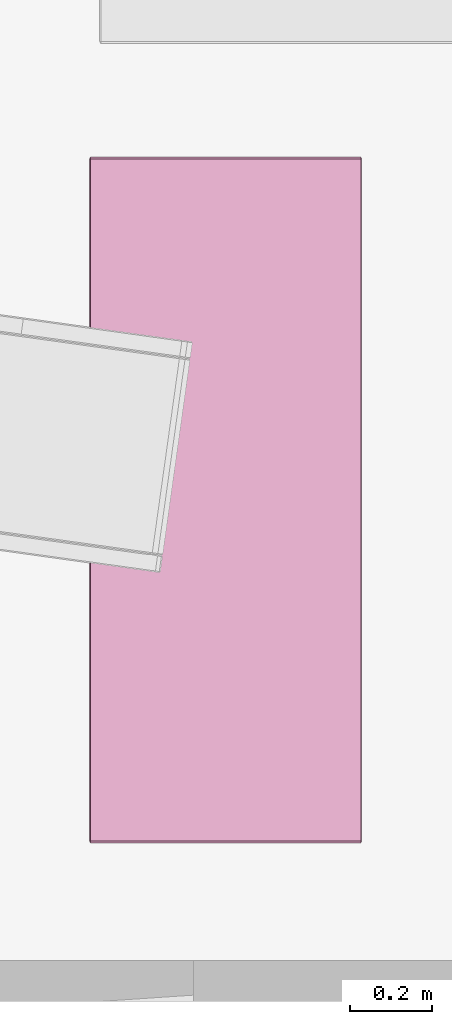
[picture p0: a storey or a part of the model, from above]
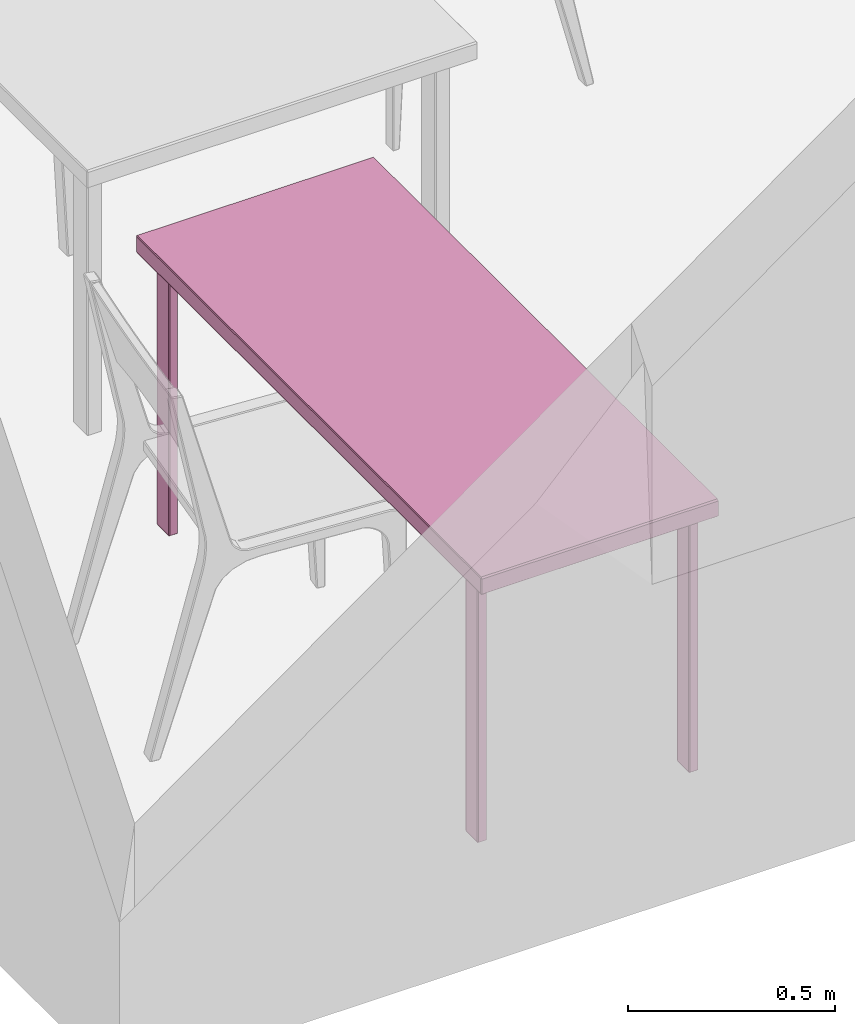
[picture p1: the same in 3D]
Properties of the parts of a building model (IFC4)

# File
Description: ViewDefinition [CoordinationView]
Time: 2025-05-14T07:05:29
Author: Metaroom
Written by: IfcOpenShell v0.7.0-f7c03db75
Made in: INDUSTRY_FOUNDATION_CLASSES_4

# IfcSite, Site
MetaroomProperties - NorthHeading: (np.float64(0.996), np.float64(-0.093), np.float64(0.0)); UpVector: (np.float64(0.0), np.float64(0.0), np.float64(1.0)); IsLeftHandedCoordinateSystem: no

# IfcBuilding, Building
Pset_BuildingCommon - NumberOfStoreys: 1

# IfcBuildingStorey, Story 0
In: Building
Elevation: 0.05 m
Pset_BuildingStoreyCommon - EntranceLevel: no; GrossPlannedArea: 0 m2; NetPlannedArea: 0 m2
Qto_BuildingStoreyBaseQuantities - GrossHeight: 0 m; NetHeight: 0 m; GrossPerimeter: 0 m; GrossFloorArea: 0 m2; NetFloorArea: 0 m2; GrossVolume: 0; NetVolume: 0

# IfcSpace (21)
In: Story 0
Type - PredefinedType: SPACE
Name
001
002
003
004
005
006
007
008
009
010
011
012
013
014
015
016
017
018
019
020
021

# IfcDoor: Metaroom Door area (23)
In: Story 0
Type - PredefinedType: DOOR
Name | OverallHeight (m) | OverallWidth (m)
Metaroom Door area | 2.49676 | 1.08286
Metaroom Door area | 2.51797 | 1.03014
Metaroom Door area | 2.28598 | 0.902772
Metaroom Door area | 2.40103 | 0.890962
Metaroom Door area | 2.49056 | 1.32274
Metaroom Door area | 2.51467 | 3.69538
Metaroom Door area | 2.50352 | 0.994197
Metaroom Door area | 2.50352 | 2.24196
Metaroom Door area | 2.51561 | 3.56465
Metaroom Door area | 2.43176 | 1.0385
Metaroom Door area | 2.445 | 1.57621
Metaroom Door area | 2.5074 | 0.955003
Metaroom Door area | 2.45179 | 1.11105
Metaroom Door area | 2.4623 | 0.965715
Metaroom Door area | 2.39817 | 1.01151
Metaroom Door area | 2.47438 | 0.897741
Metaroom Door area | 2.48644 | 0.876622
Metaroom Door area | 2.32815 | 1.05192
Metaroom Door area | 2.49795 | 1.08609
Metaroom Door area | 2.05067 | 0.6574
Metaroom Door area | 2.36662 | 1.51862
Metaroom Door area | 2.4198 | 1.28056
Metaroom Door area | 2.17628 | 0.864454

# IfcFurniture: Chair (69)
Type - ElementType: Chair; PredefinedType: USERDEFINED
Name | In
2 x Chair | 001
4 x Chair | 003
13 x Chair | 004
4 x Chair | 008
4 x Chair | 010
3 x Chair | 012
3 x Chair | 013
2 x Chair | 014
4 x Chair | 016
21 x Chair | 017
2 x Chair | 019
7 x Chair | 021

# IfcFurniture: Oven
In: 004
Type - ElementType: Oven; PredefinedType: USERDEFINED

# IfcFurniture: Refrigerator
In: 004
Type - ElementType: Refrigerator; PredefinedType: USERDEFINED

# IfcFurniture: Sink (3)
Type - ElementType: Sink; PredefinedType: USERDEFINED
Name | In
Sink | 004
Sink | 007
Sink | 011

# IfcFurniture: Storage (16)
Type - ElementType: Storage; PredefinedType: USERDEFINED
Name | In
6 x Storage | 004
2 x Storage | 005
Storage | 007
Storage | 011
Storage | 012
3 x Storage | 014
Storage | 016
Storage | 021

# IfcFurniture: Stove
In: 004
Type - ElementType: Stove; PredefinedType: USERDEFINED

# IfcFurniture: Table (18)
Type - ElementType: Table; PredefinedType: USERDEFINED
Name | In
Table | 001
Table | 003
3 x Table | 004
Table | 008
2 x Table | 010
2 x Table | 012
2 x Table | 013
Table | 014
Table | 016
Table | 017
Table | 019
2 x Table | 021

# IfcFurniture: Television (3)
Type - ElementType: Television; PredefinedType: USERDEFINED
Name | In
Television | 004
Television | 017
Television | 021

# IfcFurniture: Toilet (3)
Type - ElementType: Toilet; PredefinedType: USERDEFINED
Name | In
Toilet | 002
Toilet | 006
Toilet | 018

# IfcOpeningElement: OPENING (42)
In: Story 0
Qto_OpeningElementBaseQuantities - Volume: 0
Name | Width (m) | Height (m) | Perimeter (m) | Area (m2)
Metaroom Opening | 1.56169 | 2.24893 | 7.62124 | 3.51213
Metaroom Opening | 2.49676 | 1.08286 | 7.15923 | 2.70363
Metaroom Opening | 2.45198 | 0.854699 | 6.61336 | 2.09571
Metaroom Opening | 1.61696 | 3.99207 | 11.2181 | 6.45503
Metaroom Opening | 2.51797 | 1.03014 | 7.09621 | 2.59386
Metaroom Opening | 2.5816 | 2.47385 | 10.1109 | 6.38649
Metaroom Opening | 2.28598 | 0.902772 | 6.37751 | 2.06372
Metaroom Opening | 2.40104 | 0.890962 | 6.58399 | 2.13923
Metaroom Opening | 3.27666 | 1.63146 | 9.81625 | 5.34576
Metaroom Opening | 2.49056 | 1.32274 | 7.62661 | 3.29437
Metaroom Opening | 2.51467 | 3.69538 | 12.4201 | 9.29267
Metaroom Opening | 2.50352 | 0.994197 | 6.99544 | 2.48899
Metaroom Opening | 2.50352 | 2.24196 | 9.49096 | 5.61279
Metaroom Opening | 2.51561 | 3.56465 | 12.1605 | 8.96726
Metaroom Opening | 2.43176 | 1.0385 | 6.94052 | 2.52539
Metaroom Opening | 2.445 | 1.57621 | 8.04243 | 3.85385
Metaroom Opening | 2.5074 | 0.955003 | 6.92481 | 2.39458
Metaroom Opening | 1.11105 | 2.45179 | 7.12567 | 2.72406
Metaroom Opening | 2.4623 | 0.965715 | 6.85604 | 2.37788
Metaroom Opening | 2.39817 | 1.01151 | 6.81937 | 2.42578
Metaroom Opening | 2.47438 | 0.897741 | 6.74424 | 2.22135
Metaroom Opening | 2.48644 | 0.876622 | 6.72613 | 2.17967
Metaroom Opening | 2.32815 | 1.05192 | 6.76013 | 2.44902
Metaroom Opening | 2.49795 | 1.08609 | 7.16808 | 2.713
Metaroom Opening | 2.49261 | 0.685867 | 6.35696 | 1.7096
Metaroom Opening | 2.05067 | 0.6574 | 5.41614 | 1.34811
Metaroom Opening | 2.33859 | 1.53574 | 7.74867 | 3.59148
Metaroom Opening | 1.83275 | 1.64154 | 6.94858 | 3.00853
Metaroom Opening | 2.583 | 1.63082 | 8.42765 | 4.21242
Metaroom Opening | 1.67182 | 2.45019 | 8.24401 | 4.09627
Metaroom Opening | 1.5942 | 2.42701 | 8.04241 | 3.86913
Metaroom Opening | 1.62019 | 2.30313 | 7.84664 | 3.73151
Metaroom Opening | 1.59695 | 2.4703 | 8.13449 | 3.94493
Metaroom Opening | 1.64854 | 2.34458 | 7.98623 | 3.86513
Metaroom Opening | 1.59591 | 2.44464 | 8.0811 | 3.90143
Metaroom Opening | 1.61033 | 2.35906 | 7.93879 | 3.79887
Metaroom Opening | 1.57164 | 2.41707 | 7.97744 | 3.79878
Metaroom Opening | 1.57098 | 2.30545 | 7.75287 | 3.62182
Metaroom Opening | 1.51862 | 2.36662 | 7.7705 | 3.59402
Metaroom Opening | 2.4198 | 1.28056 | 7.4007 | 3.09868
Metaroom Opening | 2.17628 | 0.864454 | 6.08146 | 1.88129
Metaroom Opening | 1.61523 | 3.85811 | 10.9467 | 6.23173

# IfcSlab: Metaroom Ceiling (21)
In: Story 0
Type - PredefinedType: ROOF

# IfcSlab: Metaroom Slab (21)
In: Story 0
Type - PredefinedType: FLOOR

# IfcWallStandardCase: Metaroom Wall (98)
In: Story 0
Type - PredefinedType: STANDARD
Pset_WallCommon - IsExternal: no; ExtendToStructure: yes
Qto_WallBaseQuantities - Width: 0 m; GrossSideArea: 0 m2; NetSideArea: 0 m2; GrossVolume: 0; NetVolume: 0; GrossWeight: 0; NetWeight: 0
Name | Length (m) | Height (m) | GrossFootprintArea (m2) | NetFootprintArea (m2)
Wall | 4.04293 | 2.57294 | 10.4022 | 6.89009
Wall | 4.04166 | 2.57294 | 10.399 | 7.69532
2 x Wall | 3.94191 | 2.57294 | 10.1423 | 10.1423
Wall | 2.57294 | 3.94191 | 10.1423 | 10.1423
Wall | 2.57294 | 1.32092 | 3.39865 | 3.39865
Wall | 1.04863 | 2.57294 | 2.69806 | 0.602355
Wall | 2.02841 | 2.57294 | 5.21898 | 5.21898
Wall | 2.57294 | 1.21393 | 3.12338 | 3.12338
Wall | 2.57294 | 1.15562 | 2.97334 | 2.97334
Wall | 2.57294 | 3.8563 | 9.92202 | 9.92202
Wall | 0.979451 | 2.57294 | 2.52007 | 2.52007
Wall | 1.82789 | 2.57294 | 4.70304 | 4.70304
Wall | 5.55104 | 2.57294 | 14.2825 | 14.2825
Wall | 5.50147 | 2.57294 | 14.155 | 14.155
Wall | 4.16576 | 2.57294 | 10.7183 | 4.26322
Wall | 2.57294 | 4.16547 | 10.7175 | 1.73715
Wall | 2.57294 | 1.95834 | 5.0387 | 2.97498
Wall | 0.363936 | 2.57294 | 0.936384 | 0.936384
Wall | 2.57294 | 8.76216 | 22.5445 | 20.4053
Wall | 2.57294 | 1.22818 | 3.16003 | 3.16003
Wall | 3.95385 | 2.57294 | 10.173 | 4.82725
Wall | 2.57294 | 1.40518 | 3.61545 | 0.321079
Wall | 2.57294 | 1.13855 | 2.92943 | 2.92943
Wall | 2.57294 | 3.71418 | 9.55635 | 0.263684
Wall | 3.20885 | 2.57294 | 8.25618 | 5.76718
Wall | 4.2027 | 2.57294 | 10.8133 | 5.20051
Wall | 4.91329 | 2.57294 | 12.6416 | 3.67434
Wall | 2.57294 | 1.76129 | 4.53168 | 2.00629
Wall | 2.57294 | 1.98937 | 5.11853 | 1.26468
Wall | 2.57294 | 1.1564 | 2.97536 | 2.97536
Wall | 2.57294 | 2.05931 | 5.29847 | 2.90389
Wall | 2.57294 | 0.232698 | 0.598719 | 0.598719
Wall | 2.57294 | 1.32924 | 3.42004 | 0.695984
Wall | 2.57294 | 1.41443 | 3.63924 | 3.63924
Wall | 4.04463 | 2.57294 | 10.4066 | 8.0287
Wall | 0.331715 | 2.57294 | 0.853483 | 0.853483
Wall | 2.57294 | 0.536488 | 1.38035 | 1.38035
Wall | 2.57294 | 1.41442 | 3.63923 | 3.63923
Wall | 2.57294 | 1.12352 | 2.89076 | 2.89076
Wall | 2.57294 | 2.02841 | 5.21898 | 2.7932
Wall | 5.52417 | 2.57294 | 14.2134 | 14.2134
Wall | 1.82788 | 2.57294 | 4.70304 | 4.70304
Wall | 0.145565 | 2.57294 | 0.374529 | 0.374529
Wall | 2.57294 | 1.85437 | 4.77119 | 2.54984
Wall | 3.35694 | 2.57294 | 8.63721 | 6.45754
Wall | 0.668525 | 2.57294 | 1.72007 | 1.72007
Wall | 2.57294 | 2.21148 | 5.68999 | 3.24097
Wall | 2.57294 | 4.20549 | 10.8205 | 8.10747
Wall | 4.89792 | 2.57294 | 12.6021 | 12.6021
Wall | 2.57294 | 1.76129 | 4.53168 | 4.53168
Wall | 3.50811 | 2.57294 | 9.02615 | 9.02615
Wall | 2.18719 | 2.57294 | 5.6275 | 5.6275
Wall | 2.57294 | 0.126683 | 0.325949 | 0.325949
Wall | 0.119557 | 2.57294 | 0.307614 | 0.307614
Wall | 1.95834 | 2.57294 | 5.0387 | 5.0387
Wall | 1.95834 | 2.57294 | 5.03869 | 5.03869
Wall | 0.996839 | 2.57294 | 2.56481 | 0.855205
Wall | 1.13855 | 2.57294 | 2.92943 | 1.58132
Wall | 2.57294 | 2.01718 | 5.19009 | 5.19009
Wall | 5.52417 | 2.57294 | 14.2134 | 10.6219
Wall | 5.37413 | 2.57294 | 13.8273 | 6.60635
Wall | 2.57294 | 1.15641 | 2.97536 | 2.97536
Wall | 0.184557 | 2.57294 | 0.474855 | 0.474855
Wall | 0.232698 | 2.57294 | 0.598719 | 0.598719
Wall | 3.94687 | 2.57294 | 10.1551 | 6.0588
Wall | 1.02696 | 2.57294 | 2.64231 | 2.64231
Wall | 4.51393 | 2.57294 | 11.6141 | 11.6141
Wall | 1.9591 | 2.57294 | 5.04065 | 5.04065
Wall | 0.933695 | 2.57294 | 2.40234 | 2.40234
Wall | 2.01476 | 2.57294 | 5.18386 | 5.18386
Wall | 1.31352 | 2.57294 | 3.3796 | 3.3796
Wall | 0.30586 | 2.57294 | 0.78696 | 0.78696
Wall | 0.841321 | 2.57294 | 2.16467 | 2.16467
Wall | 2.57294 | 3.29423 | 8.47586 | 8.47586
Wall | 2.57294 | 1.965 | 5.05583 | 5.05583
Wall | 5.36648 | 2.57294 | 13.8076 | 13.8076
Wall | 5.36648 | 2.57294 | 13.8076 | 9.9385
Wall | 3.9542 | 2.57294 | 10.1739 | 6.44241
Wall | 5.50147 | 2.57294 | 14.1549 | 10.21
Wall | 2.57294 | 2.09983 | 5.40273 | 5.40273
Wall | 2.57294 | 3.95205 | 10.1684 | 10.1684
Wall | 3.20886 | 2.57294 | 8.2562 | 4.39107
Wall | 4.70631 | 2.57294 | 12.109 | 12.109
Wall | 1.95888 | 2.57294 | 5.04008 | 5.04008
Wall | 2.57294 | 1.02696 | 2.64232 | 2.64232
Wall | 4.01818 | 2.57294 | 10.3385 | 10.3385
Wall | 5.54089 | 2.57294 | 14.2564 | 10.3549
Wall | 8.76216 | 2.57294 | 22.5445 | 14.9469
Wall | 2.57294 | 4.20549 | 10.8205 | 7.19865
Wall | 1.8576 | 2.57294 | 4.7795 | 4.7795
Wall | 1.95919 | 2.57294 | 5.04088 | 1.44687
Wall | 2.58979 | 2.57294 | 6.66337 | 6.66337
Wall | 5.77491 | 2.57294 | 14.8585 | 11.7598
Wall | 1.879 | 2.57294 | 4.83456 | 2.95327
Wall | 2.57294 | 0.605588 | 1.55814 | 1.55814
Wall | 4.04463 | 2.57294 | 10.4066 | 4.17485
Wall | 2.57294 | 4.94545 | 12.7243 | 12.7243

# IfcWindow: Metaroom Window area (17)
In: Story 0
Type - PredefinedType: WINDOW
OverallHeight: 1.5 m; OverallWidth: 0.5 m
